VERSION 5.7 ;
  NOWIREEXTENSIONATPIN ON ;
  DIVIDERCHAR "/" ;
  BUSBITCHARS "[]" ;
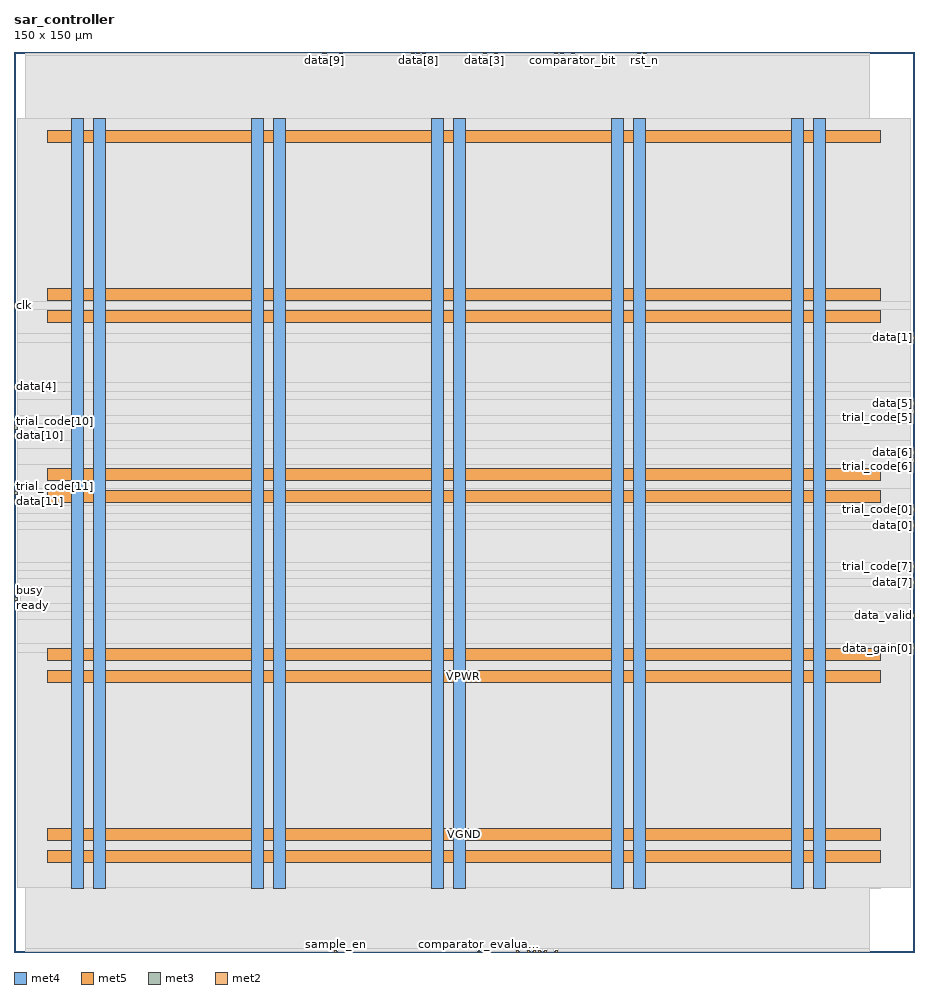
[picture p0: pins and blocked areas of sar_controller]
MACRO sar_controller
  CLASS BLOCK ;
  FOREIGN sar_controller ;
  ORIGIN 0.000 0.000 ;
  SIZE 150.000 BY 150.000 ;
  PIN VGND
    DIRECTION INOUT ;
    USE GROUND ;
    PORT
      LAYER met4 ;
        RECT 13.220 10.640 15.220 138.960 ;
    END
    PORT
      LAYER met4 ;
        RECT 43.220 10.640 45.220 138.960 ;
    END
    PORT
      LAYER met4 ;
        RECT 73.220 10.640 75.220 138.960 ;
    END
    PORT
      LAYER met4 ;
        RECT 103.220 10.640 105.220 138.960 ;
    END
    PORT
      LAYER met4 ;
        RECT 133.220 10.640 135.220 138.960 ;
    END
    PORT
      LAYER met5 ;
        RECT 5.520 18.580 144.440 20.580 ;
    END
    PORT
      LAYER met5 ;
        RECT 5.520 48.580 144.440 50.580 ;
    END
    PORT
      LAYER met5 ;
        RECT 5.520 78.580 144.440 80.580 ;
    END
    PORT
      LAYER met5 ;
        RECT 5.520 108.580 144.440 110.580 ;
    END
  END VGND
  PIN VPWR
    DIRECTION INOUT ;
    USE POWER ;
    PORT
      LAYER met4 ;
        RECT 9.520 10.640 11.520 138.960 ;
    END
    PORT
      LAYER met4 ;
        RECT 39.520 10.640 41.520 138.960 ;
    END
    PORT
      LAYER met4 ;
        RECT 69.520 10.640 71.520 138.960 ;
    END
    PORT
      LAYER met4 ;
        RECT 99.520 10.640 101.520 138.960 ;
    END
    PORT
      LAYER met4 ;
        RECT 129.520 10.640 131.520 138.960 ;
    END
    PORT
      LAYER met5 ;
        RECT 5.520 14.880 144.440 16.880 ;
    END
    PORT
      LAYER met5 ;
        RECT 5.520 44.880 144.440 46.880 ;
    END
    PORT
      LAYER met5 ;
        RECT 5.520 74.880 144.440 76.880 ;
    END
    PORT
      LAYER met5 ;
        RECT 5.520 104.880 144.440 106.880 ;
    END
    PORT
      LAYER met5 ;
        RECT 5.520 134.880 144.440 136.880 ;
    END
  END VPWR
  PIN busy
    DIRECTION OUTPUT ;
    USE SIGNAL ;
    ANTENNADIFFAREA 0.445500 ;
    PORT
      LAYER met3 ;
        RECT 0.000 59.880 0.600 60.480 ;
    END
  END busy
  PIN clk
    DIRECTION INPUT ;
    USE SIGNAL ;
    ANTENNAGATEAREA 1.704000 ;
    PORT
      LAYER met3 ;
        RECT 0.000 107.480 0.600 108.080 ;
    END
  END clk
  PIN comparator_bit
    DIRECTION INPUT ;
    USE SIGNAL ;
    ANTENNAGATEAREA 0.159000 ;
    PORT
      LAYER met2 ;
        RECT 93.010 149.720 93.290 150.000 ;
    END
  END comparator_bit
  PIN comparator_evaluate
    DIRECTION OUTPUT ;
    USE SIGNAL ;
    ANTENNADIFFAREA 0.445500 ;
    PORT
      LAYER met2 ;
        RECT 77.370 0.000 77.650 0.280 ;
    END
  END comparator_evaluate
  PIN data[0]
    DIRECTION OUTPUT ;
    USE SIGNAL ;
    ANTENNADIFFAREA 0.445500 ;
    PORT
      LAYER met3 ;
        RECT 149.400 70.760 150.000 71.360 ;
    END
  END data[0]
  PIN data[10]
    DIRECTION OUTPUT ;
    USE SIGNAL ;
    ANTENNADIFFAREA 0.445500 ;
    PORT
      LAYER met3 ;
        RECT 0.000 85.720 0.600 86.320 ;
    END
  END data[10]
  PIN data[11]
    DIRECTION OUTPUT ;
    USE SIGNAL ;
    ANTENNADIFFAREA 0.445500 ;
    PORT
      LAYER met3 ;
        RECT 0.000 74.840 0.600 75.440 ;
    END
  END data[11]
  PIN data[1]
    DIRECTION OUTPUT ;
    USE SIGNAL ;
    ANTENNADIFFAREA 0.445500 ;
    PORT
      LAYER met3 ;
        RECT 149.400 102.040 150.000 102.640 ;
    END
  END data[1]
  PIN data[2]
    DIRECTION OUTPUT ;
    USE SIGNAL ;
    ANTENNADIFFAREA 0.445500 ;
    PORT
      LAYER met2 ;
        RECT 90.250 149.720 90.530 150.000 ;
    END
  END data[2]
  PIN data[3]
    DIRECTION OUTPUT ;
    USE SIGNAL ;
    ANTENNADIFFAREA 0.445500 ;
    PORT
      LAYER met2 ;
        RECT 78.290 149.720 78.570 150.000 ;
    END
  END data[3]
  PIN data[4]
    DIRECTION OUTPUT ;
    USE SIGNAL ;
    ANTENNADIFFAREA 0.445500 ;
    PORT
      LAYER met3 ;
        RECT 0.000 93.880 0.600 94.480 ;
    END
  END data[4]
  PIN data[5]
    DIRECTION OUTPUT ;
    USE SIGNAL ;
    ANTENNADIFFAREA 0.445500 ;
    PORT
      LAYER met3 ;
        RECT 149.400 91.160 150.000 91.760 ;
    END
  END data[5]
  PIN data[6]
    DIRECTION OUTPUT ;
    USE SIGNAL ;
    ANTENNADIFFAREA 0.445500 ;
    PORT
      LAYER met3 ;
        RECT 149.400 83.000 150.000 83.600 ;
    END
  END data[6]
  PIN data[7]
    DIRECTION OUTPUT ;
    USE SIGNAL ;
    ANTENNADIFFAREA 0.445500 ;
    PORT
      LAYER met3 ;
        RECT 149.400 61.240 150.000 61.840 ;
    END
  END data[7]
  PIN data[8]
    DIRECTION OUTPUT ;
    USE SIGNAL ;
    ANTENNADIFFAREA 0.445500 ;
    PORT
      LAYER met2 ;
        RECT 67.250 149.720 67.530 150.000 ;
    END
  END data[8]
  PIN data[9]
    DIRECTION OUTPUT ;
    USE SIGNAL ;
    ANTENNADIFFAREA 0.445500 ;
    PORT
      LAYER met2 ;
        RECT 51.610 149.720 51.890 150.000 ;
    END
  END data[9]
  PIN data_gain[0]
    DIRECTION OUTPUT ;
    USE SIGNAL ;
    ANTENNADIFFAREA 0.445500 ;
    PORT
      LAYER met3 ;
        RECT 149.400 50.360 150.000 50.960 ;
    END
  END data_gain[0]
  PIN data_gain[1]
    DIRECTION OUTPUT ;
    USE SIGNAL ;
    ANTENNADIFFAREA 0.445500 ;
    PORT
      LAYER met2 ;
        RECT 88.410 0.000 88.690 0.280 ;
    END
  END data_gain[1]
  PIN data_valid
    DIRECTION OUTPUT ;
    USE SIGNAL ;
    ANTENNADIFFAREA 0.445500 ;
    PORT
      LAYER met3 ;
        RECT 149.400 55.800 150.000 56.400 ;
    END
  END data_valid
  PIN gain_latched[0]
    DIRECTION OUTPUT ;
    USE SIGNAL ;
    ANTENNADIFFAREA 0.445500 ;
    PORT
      LAYER met2 ;
        RECT 90.250 0.000 90.530 0.280 ;
    END
  END gain_latched[0]
  PIN gain_latched[1]
    DIRECTION OUTPUT ;
    USE SIGNAL ;
    ANTENNADIFFAREA 0.445500 ;
    PORT
      LAYER met2 ;
        RECT 86.570 0.000 86.850 0.280 ;
    END
  END gain_latched[1]
  PIN gain_sel[0]
    DIRECTION INPUT ;
    USE SIGNAL ;
    ANTENNAGATEAREA 0.159000 ;
    PORT
      LAYER met2 ;
        RECT 87.490 0.000 87.770 0.280 ;
    END
  END gain_sel[0]
  PIN gain_sel[1]
    DIRECTION INPUT ;
    USE SIGNAL ;
    ANTENNAGATEAREA 0.159000 ;
    PORT
      LAYER met2 ;
        RECT 85.650 0.000 85.930 0.280 ;
    END
  END gain_sel[1]
  PIN ready
    DIRECTION OUTPUT ;
    USE SIGNAL ;
    ANTENNADIFFAREA 0.445500 ;
    PORT
      LAYER met3 ;
        RECT 0.000 58.520 0.600 59.120 ;
    END
  END ready
  PIN rst_n
    DIRECTION INPUT ;
    USE SIGNAL ;
    ANTENNAGATEAREA 0.159000 ;
    PORT
      LAYER met2 ;
        RECT 104.970 149.720 105.250 150.000 ;
    END
  END rst_n
  PIN sample_en
    DIRECTION OUTPUT ;
    USE SIGNAL ;
    ANTENNADIFFAREA 0.445500 ;
    PORT
      LAYER met2 ;
        RECT 53.450 0.000 53.730 0.280 ;
    END
  END sample_en
  PIN start
    DIRECTION INPUT ;
    USE SIGNAL ;
    ANTENNAGATEAREA 0.159000 ;
    PORT
      LAYER met2 ;
        RECT 83.810 0.000 84.090 0.280 ;
    END
  END start
  PIN trial_code[0]
    DIRECTION OUTPUT ;
    USE SIGNAL ;
    ANTENNADIFFAREA 0.445500 ;
    PORT
      LAYER met3 ;
        RECT 149.400 73.480 150.000 74.080 ;
    END
  END trial_code[0]
  PIN trial_code[10]
    DIRECTION OUTPUT ;
    USE SIGNAL ;
    ANTENNADIFFAREA 0.445500 ;
    PORT
      LAYER met3 ;
        RECT 0.000 87.080 0.600 87.680 ;
    END
  END trial_code[10]
  PIN trial_code[11]
    DIRECTION OUTPUT ;
    USE SIGNAL ;
    ANTENNADIFFAREA 0.445500 ;
    PORT
      LAYER met3 ;
        RECT 0.000 76.200 0.600 76.800 ;
    END
  END trial_code[11]
  PIN trial_code[1]
    DIRECTION OUTPUT ;
    USE SIGNAL ;
    ANTENNADIFFAREA 0.445500 ;
    PORT
      LAYER met2 ;
        RECT 104.050 149.720 104.330 150.000 ;
    END
  END trial_code[1]
  PIN trial_code[2]
    DIRECTION OUTPUT ;
    USE SIGNAL ;
    ANTENNADIFFAREA 0.445500 ;
    PORT
      LAYER met2 ;
        RECT 91.170 149.720 91.450 150.000 ;
    END
  END trial_code[2]
  PIN trial_code[3]
    DIRECTION OUTPUT ;
    USE SIGNAL ;
    ANTENNADIFFAREA 0.445500 ;
    PORT
      LAYER met2 ;
        RECT 80.130 149.720 80.410 150.000 ;
    END
  END trial_code[3]
  PIN trial_code[4]
    DIRECTION OUTPUT ;
    USE SIGNAL ;
    ANTENNADIFFAREA 0.445500 ;
    PORT
      LAYER met2 ;
        RECT 68.170 149.720 68.450 150.000 ;
    END
  END trial_code[4]
  PIN trial_code[5]
    DIRECTION OUTPUT ;
    USE SIGNAL ;
    ANTENNADIFFAREA 0.445500 ;
    PORT
      LAYER met3 ;
        RECT 149.400 89.800 150.000 90.400 ;
    END
  END trial_code[5]
  PIN trial_code[6]
    DIRECTION OUTPUT ;
    USE SIGNAL ;
    ANTENNADIFFAREA 0.445500 ;
    PORT
      LAYER met3 ;
        RECT 149.400 81.640 150.000 82.240 ;
    END
  END trial_code[6]
  PIN trial_code[7]
    DIRECTION OUTPUT ;
    USE SIGNAL ;
    ANTENNADIFFAREA 0.445500 ;
    PORT
      LAYER met3 ;
        RECT 149.400 63.960 150.000 64.560 ;
    END
  END trial_code[7]
  PIN trial_code[8]
    DIRECTION OUTPUT ;
    USE SIGNAL ;
    ANTENNADIFFAREA 0.445500 ;
    PORT
      LAYER met2 ;
        RECT 66.330 149.720 66.610 150.000 ;
    END
  END trial_code[8]
  PIN trial_code[9]
    DIRECTION OUTPUT ;
    USE SIGNAL ;
    ANTENNADIFFAREA 0.445500 ;
    PORT
      LAYER met2 ;
        RECT 54.370 149.720 54.650 150.000 ;
    END
  END trial_code[9]
  OBS
      LAYER nwell ;
        RECT 5.330 10.795 144.630 138.910 ;
      LAYER li1 ;
        RECT 5.520 10.795 144.440 138.805 ;
      LAYER met1 ;
        RECT 1.910 10.640 144.440 138.960 ;
      LAYER met2 ;
        RECT 1.930 149.440 51.330 149.720 ;
        RECT 52.170 149.440 54.090 149.720 ;
        RECT 54.930 149.440 66.050 149.720 ;
        RECT 66.890 149.440 66.970 149.720 ;
        RECT 67.810 149.440 67.890 149.720 ;
        RECT 68.730 149.440 78.010 149.720 ;
        RECT 78.850 149.440 79.850 149.720 ;
        RECT 80.690 149.440 89.970 149.720 ;
        RECT 90.810 149.440 90.890 149.720 ;
        RECT 91.730 149.440 92.730 149.720 ;
        RECT 93.570 149.440 103.770 149.720 ;
        RECT 104.610 149.440 104.690 149.720 ;
        RECT 105.530 149.440 142.510 149.720 ;
        RECT 1.930 0.560 142.510 149.440 ;
        RECT 1.930 0.070 53.170 0.560 ;
        RECT 54.010 0.070 77.090 0.560 ;
        RECT 77.930 0.070 83.530 0.560 ;
        RECT 84.370 0.070 85.370 0.560 ;
        RECT 86.210 0.070 86.290 0.560 ;
        RECT 87.130 0.070 87.210 0.560 ;
        RECT 88.050 0.070 88.130 0.560 ;
        RECT 88.970 0.070 89.970 0.560 ;
        RECT 90.810 0.070 142.510 0.560 ;
      LAYER met3 ;
        RECT 0.600 108.480 149.400 138.885 ;
        RECT 1.000 107.080 149.400 108.480 ;
        RECT 0.600 103.040 149.400 107.080 ;
        RECT 0.600 101.640 149.000 103.040 ;
        RECT 0.600 94.880 149.400 101.640 ;
        RECT 1.000 93.480 149.400 94.880 ;
        RECT 0.600 92.160 149.400 93.480 ;
        RECT 0.600 89.400 149.000 92.160 ;
        RECT 0.600 88.080 149.400 89.400 ;
        RECT 1.000 85.320 149.400 88.080 ;
        RECT 0.600 84.000 149.400 85.320 ;
        RECT 0.600 81.240 149.000 84.000 ;
        RECT 0.600 77.200 149.400 81.240 ;
        RECT 1.000 74.480 149.400 77.200 ;
        RECT 1.000 74.440 149.000 74.480 ;
        RECT 0.600 73.080 149.000 74.440 ;
        RECT 0.600 71.760 149.400 73.080 ;
        RECT 0.600 70.360 149.000 71.760 ;
        RECT 0.600 64.960 149.400 70.360 ;
        RECT 0.600 63.560 149.000 64.960 ;
        RECT 0.600 62.240 149.400 63.560 ;
        RECT 0.600 60.880 149.000 62.240 ;
        RECT 1.000 60.840 149.000 60.880 ;
        RECT 1.000 58.120 149.400 60.840 ;
        RECT 0.600 56.800 149.400 58.120 ;
        RECT 0.600 55.400 149.000 56.800 ;
        RECT 0.600 51.360 149.400 55.400 ;
        RECT 0.600 49.960 149.000 51.360 ;
        RECT 0.600 10.715 149.400 49.960 ;
  END
END sar_controller
END LIBRARY

